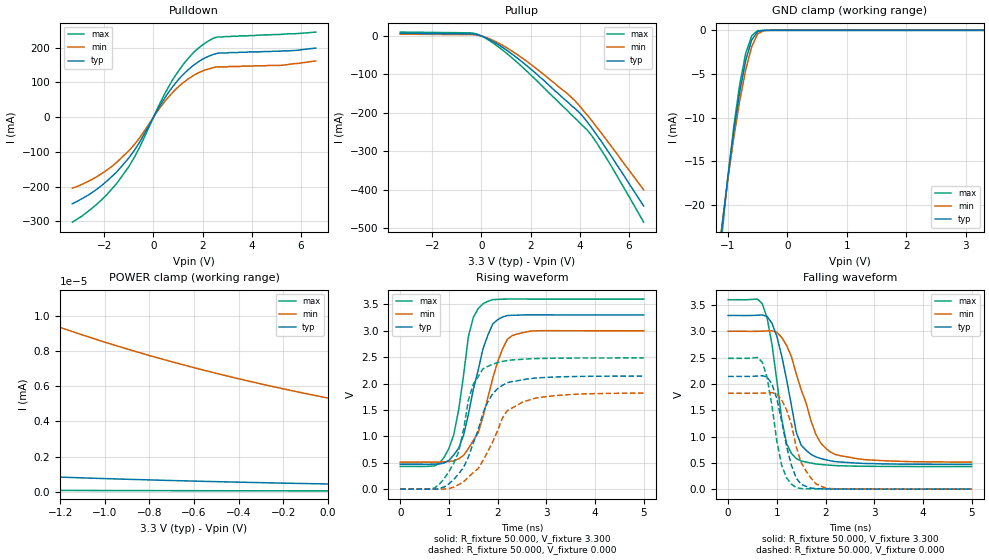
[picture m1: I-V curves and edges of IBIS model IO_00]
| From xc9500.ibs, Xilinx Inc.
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|   Model IO_00
[Model]   IO_00
Model_type   I/O
Polarity   Non-Inverting
Enable   Active-High
Vinl =   0.800V
Vinh =   2.000V
Vmeas =   1.650V
Cref =  50.000pF
Rref =   1.000M
Vref =  0.000V
C_comp   8.000pF   6.000pF   10.000pF
[Temperature Range]   50.000   100.000   0.000
[Voltage Range]   3.300V   3.000V   3.600V
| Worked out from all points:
|   slope of the pulldown table from 0 to 0.495 V, typ, clamps not added: 8.38 ohm
|   slope of the pullup table from 0 to 0.495 V, typ, clamps not added: 32.7 ohm
|   GND clamp passes 1 mA (typ) near -0.59 V on its own axis
|   POWER clamp passes 1 mA (typ) near -2.62 V on its own axis
|   rising waveform, R_fixture 50.000, V_fixture 3.300: 20-80 % time 424ps typ, 475ps min, 314ps max; typ from 0.472 V to 3.3 V
|   rising waveform, R_fixture 50.000, V_fixture 0.000: 20-80 % time 531ps typ, 609ps min, 399ps max; typ from 0 V to 2.14 V
|   falling waveform, R_fixture 50.000, V_fixture 3.300: 20-80 % time 371ps typ, 516ps min, 300ps max; typ from 3.3 V to 0.472 V
|   falling waveform, R_fixture 50.000, V_fixture 0.000: 20-80 % time 309ps typ, 369ps min, 266ps max; typ from 2.14 V to 0 V
[Pulldown]
| voltage   I(typ)   I(min)   I(max)
-3.3V     -249mA     -204mA     -302mA
-2.3V     -207mA     -171mA     -250mA
-1.5V     -158mA     -130mA     -191mA
-1V       -117mA     -96.33mA   -142mA
-700mV    -87.07mA   -71.85mA   -105mA
300mV     37.26mA    30.59mA    45.34mA
800mV     89.38mA    72.76mA    110mA
1.3V      129mA      104mA      160mA
1.9V      163mA      130mA      203mA
2.6V      184mA      145mA      231mA
5.1V      190mA      149mA      238mA
6.6V      199mA      162mA      245mA
[Pullup]
| voltage   I(typ)   I(min)   I(max)
-3.3V     6.866mA    4.62mA     10.1mA
-300mV    4.692mA    3.207mA    6.723mA
-100mV    2.086mA    1.502mA    2.882mA
200mV     -5.344mA   -4.077mA   -7.033mA
800mV     -27.08mA   -22.04mA   -33.58mA
1.9V      -80.12mA   -68.48mA   -94.62mA
3.5V      -171mA     -150mA     -194mA
4V        -200mA     -182mA     -226mA
4.3V      -223mA     -205mA     -244mA
4.5V      -240mA     -221mA     -260mA
5.1V      -295mA     -271mA     -319mA
6.6V      -442mA     -400mA     -484mA
[GND_clamp]
| voltage   I(typ)   I(min)   I(max)
-3.3V     -211mA     -187mA     -240mA
-1.1V     -22.63mA   -22.34mA   -23.43mA
-1V       -16.78mA   -17.07mA   -16.83mA
-900mV    -11.52mA   -12.27mA   -10.99mA
-800mV    -7.005mA   -8.035mA   -6.143mA
-700mV    -3.443mA   -4.508mA   -2.631mA
-600mV    -1.112mA   -1.886mA   -628uA
-500mV    -146uA     -411uA     -39.6uA
-400mV    -11.61uA   -42.16uA   -2.469uA
-300mV    -1.054uA   -5.205uA   -140nA
3.3V      432pA      6.144nA    31.96pA
[POWER_clamp]
| voltage   I(typ)   I(min)   I(max)
-3.3V     5.154mA    7.51mA     3.331mA
-2.4V     123uA      1.138mA    24.22nA
-2.3V     13.62uA    619uA      419pA
-2.2V     550nA      241uA      105pA
-2.1V     16.36nA    51.5uA     96.67pA
-2V       1.649nA    4.929uA    92.27pA
-1.9V     1.21nA     273nA      88.15pA
-1.6V     1.022nA    11.32nA    76.95pA
-1.5V     968pA      10.78nA    73.57pA
-800mV    665pA      7.766nA    53.78pA
-400mV    536pA      6.439nA    44.83pA
0V        432pA      5.338nA    37.11pA
[Ramp]
| variable   typ   min   max
dV/dt_r   1.285/0.526n   1.092/0.632n   1.492/0.424n
dV/dt_f   1.697/0.382n   1.492/0.510n   1.902/0.286n
R_load = 50.000
[Rising Waveform]
R_fixture = 50.000
V_fixture = 3.300
V_fixture_min = 3.000
V_fixture_max = 3.600
L_fixture = 0.000H
C_fixture = 0.000F
| time   V(typ)   V(min)   V(max)
0s        472mV      512mV      430mV
700ps     474mV      511mV      440mV
1ns       546mV      524mV      772mV
1.2ns     777mV      574mV      1.503V
1.4ns     1.416V     769mV      2.892V
1.5ns     1.883V     921mV      3.251V
1.7ns     2.661V     1.374V     3.513V
2ns       3.209V     2.411V     3.595V
2.3ns     3.294V     2.909V     3.601V
5ns       3.3V       3V         3.6V
[Rising Waveform]
R_fixture = 50.000
V_fixture = 0.000
V_fixture_min = 0.000
V_fixture_max = 0.000
L_fixture = 0.000H
C_fixture = 0.000F
| time   V(typ)   V(min)   V(max)
0s        0V         0V         0V
900ps     40.2mV     570uV      196mV
1.2ns     288mV      85.05mV    711mV
1.3ns     413mV      139mV      1.126V
1.5ns     875mV      313mV      1.988V
1.7ns     1.438V     543mV      2.282V
1.9ns     1.807V     898mV      2.366V
2.2ns     2.017V     1.488V     2.437V
2.5ns     2.069V     1.645V     2.46V
5ns       2.142V     1.82V      2.486V
[Falling Waveform]
R_fixture = 50.000
V_fixture = 3.300
V_fixture_min = 3.000
V_fixture_max = 3.600
L_fixture = 0.000H
C_fixture = 0.000F
| time   V(typ)   V(min)   V(max)
0s        3.3V       3V         3.6V
700ps     3.31V      3.002V     3.525V
900ps     3.151V     3.008V     2.75V
1.1ns     2.532V     2.883V     1.332V
1.2ns     2.083V     2.732V     866mV
1.4ns     1.079V     2.187V     580mV
1.5ns     836mV      1.886V     536mV
1.8ns     614mV      1.044V     480mV
2.2ns     524mV      659mV      448mV
5ns       472mV      514mV      430mV
[Falling Waveform]
R_fixture = 50.000
V_fixture = 0.000
V_fixture_min = 0.000
V_fixture_max = 0.000
L_fixture = 0.000H
C_fixture = 0.000F
| time   V(typ)   V(min)   V(max)
0s        2.142V     1.822V     2.486V
700ps     2.155V     1.824V     2.415V
800ps     2.133V     1.829V     2.123V
900ps     1.996V     1.835V     1.583V
1.1ns     1.287V     1.693V     453mV
1.3ns     452mV      1.232V     94.06mV
1.4ns     207mV      797mV      28.25mV
1.7ns     21.29mV    211mV      6.84mV
2ns       6.649mV    23.19mV    3.202mV
5ns       11.43uV    124uV      26.53uV
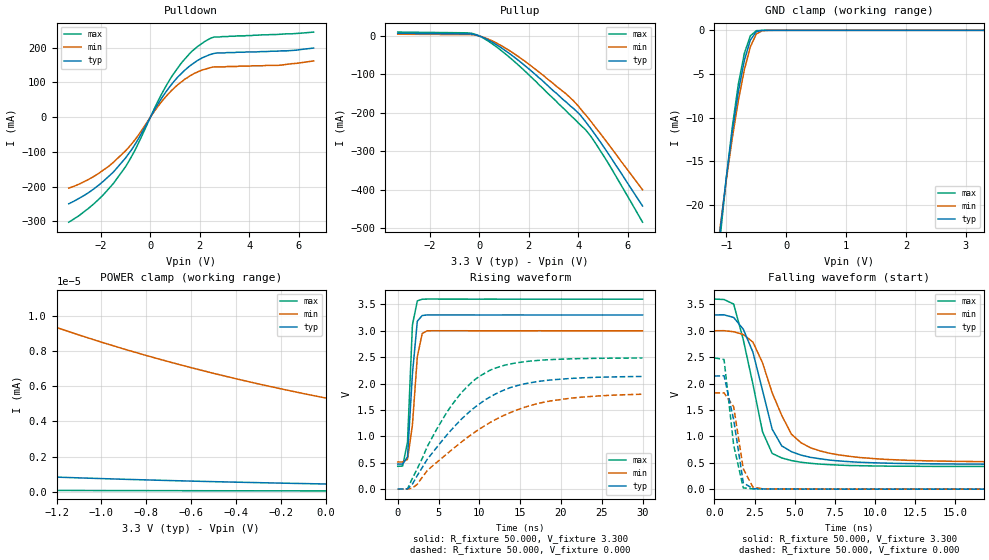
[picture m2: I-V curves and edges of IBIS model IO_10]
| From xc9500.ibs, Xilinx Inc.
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|   Model IO_10
[Model]   IO_10
Model_type   I/O
Polarity   Non-Inverting
Enable   Active-High
Vinl =   0.800V
Vinh =   2.000V
Vmeas =   1.650V
Cref =  50.000pF
Rref =   1.000M
Vref =  0.000V
C_comp   8.000pF   6.000pF   10.000pF
[Temperature Range]   50.000   100.000   0.000
[Voltage Range]   3.300V   3.000V   3.600V
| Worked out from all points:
|   slope of the pulldown table from 0 to 0.495 V, typ, clamps not added: 8.38 ohm
|   slope of the pullup table from 0 to 0.495 V, typ, clamps not added: 32.7 ohm
|   GND clamp passes 1 mA (typ) near -0.59 V on its own axis
|   POWER clamp passes 1 mA (typ) near -2.62 V on its own axis
|   rising waveform, R_fixture 50.000, V_fixture 3.300: 20-80 % time 768ps typ, 784ps min, 513ps max; typ from 0.472 V to 3.3 V
|   rising waveform, R_fixture 50.000, V_fixture 0.000: 20-80 % time 7.81ns typ, 9.92ns min, 6.08ns max; typ from 0 V to 2.13 V
|   falling waveform, R_fixture 50.000, V_fixture 3.300: 20-80 % time 1.58ns typ, 2.09ns min, 1.36ns max; typ from 3.3 V to 0.472 V
|   falling waveform, R_fixture 50.000, V_fixture 0.000: 20-80 % time 733ps typ, 583ps min, 677ps max; typ from 2.14 V to 0 V
[Pulldown]
| voltage   I(typ)   I(min)   I(max)
-3.3V     -249mA     -204mA     -302mA
-2.3V     -207mA     -171mA     -250mA
-1.5V     -158mA     -130mA     -191mA
-1V       -117mA     -96.33mA   -142mA
-700mV    -87.07mA   -71.85mA   -105mA
300mV     37.26mA    30.59mA    45.34mA
800mV     89.38mA    72.75mA    110mA
1.3V      129mA      104mA      160mA
1.9V      163mA      130mA      203mA
2.6V      184mA      145mA      231mA
5.1V      190mA      149mA      238mA
6.6V      199mA      162mA      245mA
[Pullup]
| voltage   I(typ)   I(min)   I(max)
-3.3V     6.866mA    4.62mA     10.1mA
-300mV    4.692mA    3.206mA    6.723mA
-100mV    2.086mA    1.502mA    2.882mA
200mV     -5.344mA   -4.077mA   -7.033mA
800mV     -27.08mA   -22.04mA   -33.58mA
1.9V      -80.12mA   -68.48mA   -94.62mA
3.5V      -171mA     -150mA     -194mA
4V        -200mA     -182mA     -226mA
4.3V      -223mA     -205mA     -244mA
4.5V      -240mA     -221mA     -260mA
5.1V      -295mA     -271mA     -319mA
6.6V      -442mA     -400mA     -484mA
[GND_clamp]
| voltage   I(typ)   I(min)   I(max)
-3.3V     -211mA     -187mA     -240mA
-1.1V     -22.63mA   -22.34mA   -23.43mA
-1V       -16.78mA   -17.07mA   -16.83mA
-900mV    -11.52mA   -12.27mA   -10.99mA
-800mV    -7.005mA   -8.035mA   -6.143mA
-700mV    -3.443mA   -4.508mA   -2.631mA
-600mV    -1.112mA   -1.886mA   -628uA
-500mV    -146uA     -411uA     -39.6uA
-400mV    -11.61uA   -42.16uA   -2.469uA
-300mV    -1.054uA   -5.205uA   -140nA
3.3V      432pA      6.144nA    31.96pA
[POWER_clamp]
| voltage   I(typ)   I(min)   I(max)
-3.3V     5.154mA    7.51mA     3.331mA
-2.4V     123uA      1.138mA    24.22nA
-2.3V     13.62uA    619uA      419pA
-2.2V     550nA      241uA      105pA
-2.1V     16.36nA    51.5uA     96.67pA
-2V       1.649nA    4.929uA    92.27pA
-1.9V     1.21nA     273nA      88.15pA
-1.6V     1.022nA    11.32nA    76.95pA
-1.5V     968pA      10.78nA    73.57pA
-800mV    665pA      7.766nA    53.78pA
-400mV    536pA      6.439nA    44.83pA
0V        432pA      5.338nA    37.11pA
[Ramp]
| variable   typ   min   max
dV/dt_r   1.280/7.938n   1.078/9.930n   1.490/6.251n
dV/dt_f   1.697/1.613n   1.493/2.185n   1.902/1.086n
R_load = 50.000
[Rising Waveform]
R_fixture = 50.000
V_fixture = 3.300
V_fixture_min = 3.000
V_fixture_max = 3.600
L_fixture = 0.000H
C_fixture = 0.000F
| time   V(typ)   V(min)   V(max)
0s        472mV      512mV      430mV
600ps     473mV      511mV      434mV
1.2ns     608mV      561mV      888mV
1.8ns     2.181V     1.212V     3.111V
2.4ns     3.181V     2.507V     3.568V
3ns       3.29V      2.948V     3.599V
3.6ns     3.301V     3V         3.602V
30ns      3.3V       3V         3.6V
[Rising Waveform]
R_fixture = 50.000
V_fixture = 0.000
V_fixture_min = 0.000
V_fixture_max = 0.000
L_fixture = 0.000H
C_fixture = 0.000F
| time   V(typ)   V(min)   V(max)
0s        -20.61uV   -20.13uV   -10.51uV
1.2ns     80.5uV     -4.061mV   3.61mV
2.4ns     256mV      88.66mV    388mV
4.2ns     675mV      428mV      971mV
7.2ns     1.226V     815mV      1.709V
9ns       1.493V     1.027V     2.014V
11.4ns    1.752V     1.268V     2.259V
14.4ns    1.95V      1.487V     2.389V
18.6ns    2.065V     1.666V     2.452V
30ns      2.134V     1.797V     2.484V
[Falling Waveform]
R_fixture = 50.000
V_fixture = 3.300
V_fixture_min = 3.000
V_fixture_max = 3.600
L_fixture = 0.000H
C_fixture = 0.000F
| time   V(typ)   V(min)   V(max)
0s        3.3V       3V         3.6V
1.2ns     3.252V     2.981V     3.505V
1.8ns     3.029V     2.929V     2.829V
2.4ns     2.594V     2.785V     1.989V
3ns       1.868V     2.393V     1.087V
3.6ns     1.137V     1.825V     677mV
4.2ns     819mV      1.396V     591mV
5.4ns     645mV      879mV      510mV
9ns       510mV      601mV      445mV
30ns      472mV      512mV      430mV
[Falling Waveform]
R_fixture = 50.000
V_fixture = 0.000
V_fixture_min = 0.000
V_fixture_max = 0.000
L_fixture = 0.000H
C_fixture = 0.000F
| time   V(typ)   V(min)   V(max)
0s        2.142V     1.822V     2.486V
600ps     2.148V     1.824V     2.455V
1.2ns     1.313V     1.561V     833mV
1.8ns     121mV      385mV      24.09mV
2.4ns     9.881mV    36.98mV    5.526mV
3ns       4.485mV    7.228mV    3.735mV
30ns      1.589uV    4.522uV    0V
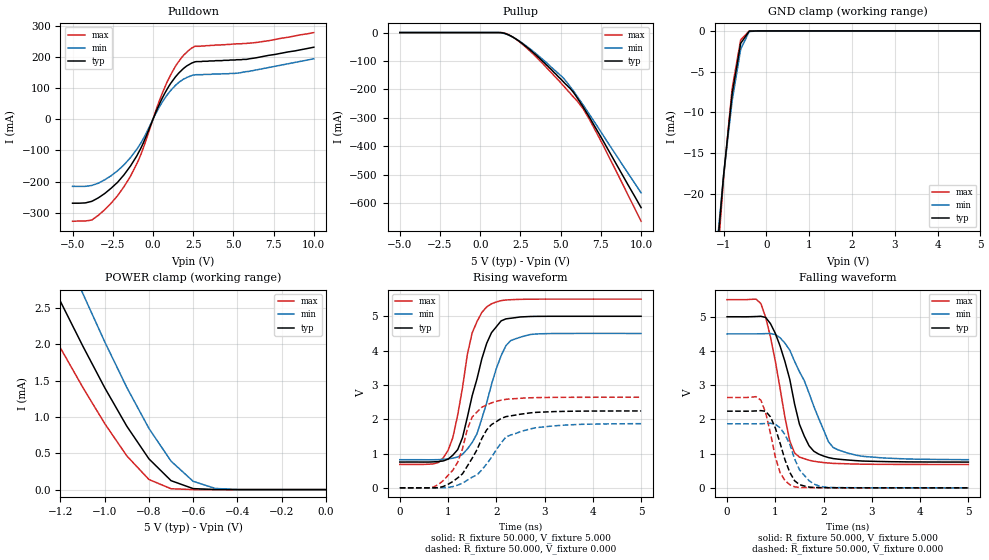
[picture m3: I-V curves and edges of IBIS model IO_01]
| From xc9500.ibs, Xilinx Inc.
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|   Model IO_01
[Model]   IO_01
Model_type   I/O
Polarity   Non-Inverting
Enable   Active-High
Vinl =   0.800V
Vinh =   2.000V
Vmeas =   2.500V
Cref =  50.000pF
Rref =   1.000M
Vref =  0.000V
C_comp   8.000pF   6.000pF   10.000pF
[Temperature Range]   50.000   100.000   0.000
[Voltage Range]   5.000V   4.500V   5.500V
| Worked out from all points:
|   slope of the pulldown table from 0 to 0.75 V, typ, clamps not added: 8.86 ohm
|   GND clamp passes 1 mA (typ) near -0.53 V on its own axis
|   POWER clamp passes 1 mA (typ) near -0.92 V on its own axis
|   rising waveform, R_fixture 50.000, V_fixture 5.000: 20-80 % time 464ps typ, 485ps min, 379ps max; typ from 0.752 V to 5 V
|   rising waveform, R_fixture 50.000, V_fixture 0.000: 20-80 % time 550ps typ, 630ps min, 427ps max; typ from 0 V to 2.24 V
|   falling waveform, R_fixture 50.000, V_fixture 5.000: 20-80 % time 477ps typ, 660ps min, 382ps max; typ from 5 V to 0.753 V
|   falling waveform, R_fixture 50.000, V_fixture 0.000: 20-80 % time 315ps typ, 374ps min, 267ps max; typ from 2.24 V to 0 V
[Pulldown]
| voltage   I(typ)   I(min)   I(max)
-5V       -269mA     -215mA     -327mA
-3.8V     -263mA     -212mA     -323mA
-2.6V     -221mA     -181mA     -269mA
-1.8V     -178mA     -146mA     -216mA
-800mV    -97.55mA   -79.99mA   -119mA
300mV     37.26mA    30.39mA    45.54mA
900mV     98.33mA    79.25mA    122mA
1.5V      142mA      113mA      178mA
2.2V      174mA      136mA      220mA
2.6V      184mA      142mA      234mA
5.3V      191mA      148mA      242mA
10V       231mA      194mA      278mA
[Pullup]
| voltage   I(typ)   I(min)   I(max)
-5V       1.02nA     10.29nA    82.28pA
1.3V      -273uA     -843uA     -21.01uA
1.8V      -9.1mA     -9.856mA   -8.419mA
2.4V      -29.57mA   -28.78mA   -30.92mA
3.6V      -85.9mA    -80.57mA   -92.72mA
5.1V      -169mA     -156mA     -183mA
5.6V      -197mA     -191mA     -214mA
5.8V      -211mA     -206mA     -227mA
6.4V      -262mA     -255mA     -268mA
6.8V      -299mA     -289mA     -307mA
7.6V      -377mA     -358mA     -392mA
10V       -616mA     -564mA     -664mA
[GND_clamp]
| voltage   I(typ)   I(min)   I(max)
-5V       -382mA     -334mA     -435mA
-1.2V     -30.21mA   -28.94mA   -32.31mA
-1V       -17.79mA   -17.84mA   -18.17mA
-800mV    -7.754mA   -8.624mA   -7.105mA
-600mV    -1.523mA   -2.242mA   -1.096mA
-400mV    -25.36uA   -70.36uA   -7.543uA
5V        1.077nA    15.87uA    68.4pA
[POWER_clamp]
| voltage   I(typ)   I(min)   I(max)
-5V       28.53mA    33.14mA    24.98mA
-1.4V     3.852mA    4.851mA    3.071mA
-1.3V     3.213mA    4.12mA     2.503mA
-1.2V     2.588mA    3.403mA    1.948mA
-1.1V     1.981mA    2.705mA    1.412mA
-1V       1.402mA    2.034mA    909uA
-900mV    872uA      1.405mA    464uA
-800mV    423uA      842uA      139uA
-700mV    123uA      391uA      11.97uA
-600mV    13.69uA    114uA      250nA
-500mV    553nA      15.87uA    3.499nA
0V        1.077nA    10.78nA    86.2pA
[Ramp]
| variable   typ   min   max
dV/dt_r   1.344/0.535n   1.122/0.666n   1.584/0.439n
dV/dt_f   2.548/0.479n   2.206/0.639n   2.890/0.373n
R_load = 50.000
[Rising Waveform]
R_fixture = 50.000
V_fixture = 5.000
V_fixture_min = 4.500
V_fixture_max = 5.500
L_fixture = 0.000H
C_fixture = 0.000F
| time   V(typ)   V(min)   V(max)
0s        752mV      820mV      683mV
800ps     766mV      822mV      738mV
1ns       836mV      843mV      1.09V
1.1ns     953mV      864mV      1.469V
1.3ns     1.466V     976mV      2.924V
1.5ns     2.685V     1.323V     4.516V
1.8ns     4.209V     2.475V     5.272V
2.1ns     4.866V     3.852V     5.455V
2.3ns     4.942V     4.292V     5.482V
5ns       4.999V     4.499V     5.499V
[Rising Waveform]
R_fixture = 50.000
V_fixture = 0.000
V_fixture_min = 0.000
V_fixture_max = 0.000
L_fixture = 0.000H
C_fixture = 0.000F
| time   V(typ)   V(min)   V(max)
0s        0V         0V         0V
600ps     -382uV     -10.69uV   -255uV
900ps     38.65mV    374uV      211mV
1.2ns     290mV      78.77mV    746mV
1.5ns     863mV      312mV      2.065V
1.8ns     1.689V     697mV      2.415V
1.9ns     1.843V     887mV      2.476V
2.2ns     2.075V     1.482V     2.579V
2.8ns     2.197V     1.748V     2.629V
5ns       2.24V      1.87V      2.64V
[Falling Waveform]
R_fixture = 50.000
V_fixture = 5.000
V_fixture_min = 4.500
V_fixture_max = 5.500
L_fixture = 0.000H
C_fixture = 0.000F
| time   V(typ)   V(min)   V(max)
0s        5V         4.5V       5.5V
700ps     5.014V     4.502V     5.387V
900ps     4.798V     4.511V     4.405V
1.1ns     4.139V     4.385V     2.895V
1.3ns     3.168V     4.021V     1.369V
1.5ns     1.859V     3.394V     899mV
1.8ns     1.068V     2.373V     778mV
2.2ns     856mV      1.178V     715mV
2.9ns     780mV      911mV      691mV
5ns       753mV      824mV      683mV
[Falling Waveform]
R_fixture = 50.000
V_fixture = 0.000
V_fixture_min = 0.000
V_fixture_max = 0.000
L_fixture = 0.000H
C_fixture = 0.000F
| time   V(typ)   V(min)   V(max)
0s        2.241V     1.872V     2.64V
700ps     2.257V     1.874V     2.563V
800ps     2.238V     1.88V      2.197V
900ps     2.073V     1.887V     1.589V
1.1ns     1.301V     1.753V     441mV
1.3ns     453mV      1.273V     92.12mV
1.4ns     207mV      844mV      30.31mV
1.7ns     22.53mV    209mV      7.037mV
2ns       6.579mV    27.45mV    3.527mV
5ns       15.9uV     151uV      -5.869uV
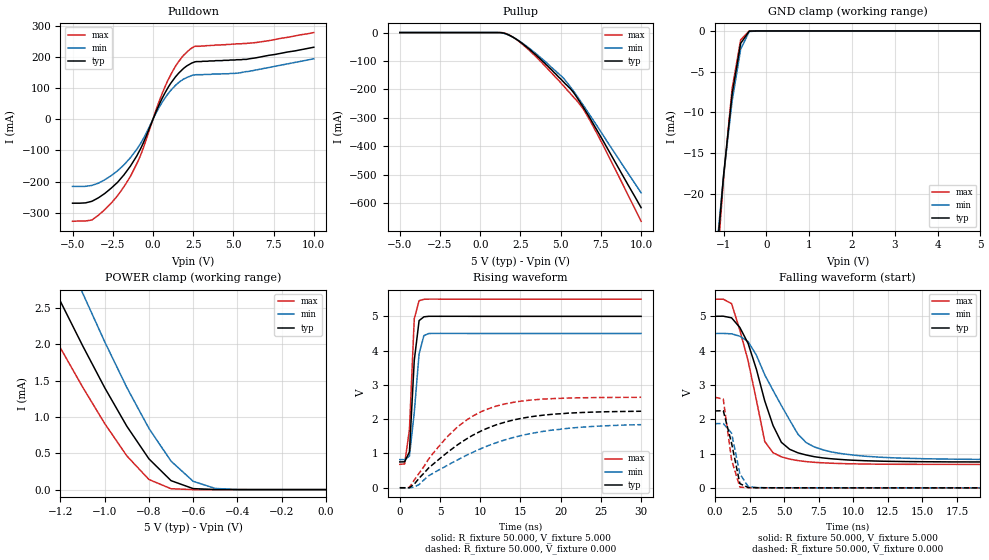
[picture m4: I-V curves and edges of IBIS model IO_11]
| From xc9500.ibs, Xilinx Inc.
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|   Model IO_11
[Model]   IO_11
Model_type   I/O
Polarity   Non-Inverting
Enable   Active-High
Vinl =   0.800V
Vinh =   2.000V
Vmeas =   2.500V
Cref =  50.000pF
Rref =   1.000M
Vref =  0.000V
C_comp   8.000pF   6.000pF   10.000pF
[Temperature Range]   50.000   100.000   0.000
[Voltage Range]   5.000V   4.500V   5.500V
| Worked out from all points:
|   slope of the pulldown table from 0 to 0.75 V, typ, clamps not added: 8.86 ohm
|   GND clamp passes 1 mA (typ) near -0.53 V on its own axis
|   POWER clamp passes 1 mA (typ) near -0.92 V on its own axis
|   rising waveform, R_fixture 50.000, V_fixture 5.000: 20-80 % time 701ps typ, 851ps min, 556ps max; typ from 0.753 V to 5 V
|   rising waveform, R_fixture 50.000, V_fixture 0.000: 20-80 % time 8.34ns typ, 10.5ns min, 6.51ns max; typ from 0 V to 2.23 V
|   falling waveform, R_fixture 50.000, V_fixture 5.000: 20-80 % time 2.02ns typ, 2.92ns min, 1.62ns max; typ from 5 V to 0.753 V
|   falling waveform, R_fixture 50.000, V_fixture 0.000: 20-80 % time 746ps typ, 604ps min, 657ps max; typ from 2.24 V to 0 V
[Pulldown]
| voltage   I(typ)   I(min)   I(max)
-5V       -269mA     -215mA     -327mA
-3.8V     -263mA     -212mA     -323mA
-2.6V     -221mA     -181mA     -269mA
-1.8V     -178mA     -146mA     -216mA
-800mV    -97.55mA   -79.99mA   -119mA
300mV     37.26mA    30.39mA    45.54mA
900mV     98.33mA    79.25mA    122mA
1.5V      142mA      113mA      178mA
2.2V      174mA      136mA      220mA
2.6V      184mA      142mA      234mA
5.3V      191mA      148mA      242mA
10V       231mA      194mA      278mA
[Pullup]
| voltage   I(typ)   I(min)   I(max)
-5V       1.02nA     10.29nA    82.28pA
1.3V      -273uA     -843uA     -21.01uA
1.8V      -9.1mA     -9.856mA   -8.419mA
2.4V      -29.57mA   -28.78mA   -30.92mA
3.6V      -85.9mA    -80.57mA   -92.72mA
5.1V      -169mA     -156mA     -183mA
5.6V      -197mA     -191mA     -214mA
5.8V      -211mA     -206mA     -227mA
6.4V      -262mA     -255mA     -268mA
6.8V      -299mA     -289mA     -307mA
7.6V      -377mA     -358mA     -392mA
10V       -616mA     -564mA     -664mA
[GND_clamp]
| voltage   I(typ)   I(min)   I(max)
-5V       -382mA     -334mA     -435mA
-1.2V     -30.21mA   -28.94mA   -32.31mA
-1V       -17.79mA   -17.84mA   -18.17mA
-800mV    -7.754mA   -8.624mA   -7.105mA
-600mV    -1.523mA   -2.242mA   -1.096mA
-400mV    -25.36uA   -70.36uA   -7.543uA
5V        1.077nA    15.87uA    68.4pA
[POWER_clamp]
| voltage   I(typ)   I(min)   I(max)
-5V       28.53mA    33.14mA    24.98mA
-1.4V     3.852mA    4.851mA    3.071mA
-1.3V     3.213mA    4.12mA     2.503mA
-1.2V     2.588mA    3.403mA    1.948mA
-1.1V     1.981mA    2.705mA    1.412mA
-1V       1.402mA    2.034mA    909uA
-900mV    872uA      1.405mA    464uA
-800mV    423uA      842uA      139uA
-700mV    123uA      391uA      11.97uA
-600mV    13.69uA    114uA      250nA
-500mV    553nA      15.87uA    3.499nA
0V        1.077nA    10.78nA    86.2pA
[Ramp]
| variable   typ   min   max
dV/dt_r   1.339/8.477n   1.104/10.471n   1.583/6.675n
dV/dt_f   2.548/2.112n   2.208/3.028n   2.890/1.536n
R_load = 50.000
[Rising Waveform]
R_fixture = 50.000
V_fixture = 5.000
V_fixture_min = 4.500
V_fixture_max = 5.500
L_fixture = 0.000H
C_fixture = 0.000F
| time   V(typ)   V(min)   V(max)
0s        753mV      820mV      683mV
600ps     756mV      819mV      694mV
1.2ns     1.045V     923mV      1.695V
1.8ns     3.71V      2.192V     4.928V
2.4ns     4.875V     3.906V     5.456V
3ns       4.986V     4.44V      5.497V
3.6ns     5.001V     4.499V     5.502V
30ns      5V         4.5V       5.5V
[Rising Waveform]
R_fixture = 50.000
V_fixture = 0.000
V_fixture_min = 0.000
V_fixture_max = 0.000
L_fixture = 0.000H
C_fixture = 0.000F
| time   V(typ)   V(min)   V(max)
0s        -21.94uV   -21.46uV   -11.52uV
1.2ns     3.031mV    -3.212mV   8.709mV
2.4ns     278mV      93.86mV    423mV
4.2ns     698mV      432mV      1.022V
7.2ns     1.255V     815mV      1.778V
9ns       1.522V     1.025V     2.082V
10.8ns    1.727V     1.209V     2.284V
14.4ns    1.989V     1.483V     2.502V
18.6ns    2.134V     1.671V     2.595V
30ns      2.231V     1.84V      2.638V
[Falling Waveform]
R_fixture = 50.000
V_fixture = 5.000
V_fixture_min = 4.500
V_fixture_max = 5.500
L_fixture = 0.000H
C_fixture = 0.000F
| time   V(typ)   V(min)   V(max)
0s        5V         4.5V       5.5V
1.2ns     4.955V     4.489V     5.368V
1.8ns     4.673V     4.419V     4.592V
2.4ns     4.204V     4.261V     3.693V
3.6ns     2.532V     3.293V     1.351V
4.2ns     1.816V     2.84V      1.024V
4.8ns     1.328V     2.4V       905mV
6.6ns     957mV      1.317V     765mV
9ns       830mV      1.006V     710mV
30ns      753mV      820mV      683mV
[Falling Waveform]
R_fixture = 50.000
V_fixture = 0.000
V_fixture_min = 0.000
V_fixture_max = 0.000
L_fixture = 0.000H
C_fixture = 0.000F
| time   V(typ)   V(min)   V(max)
0s        2.241V     1.872V     2.64V
600ps     2.249V     1.874V     2.585V
1.2ns     1.301V     1.595V     816mV
1.8ns     123mV      407mV      22.07mV
2.4ns     9.705mV    38.86mV    5.345mV
3ns       4.468mV    7.918mV    3.733mV
30ns      3.496uV    5.368uV    -1.972uV
